One B-rep face of a CAD part: STEP entity #219.
In plain terms, the planar face has unit normal (1, 0, 0).
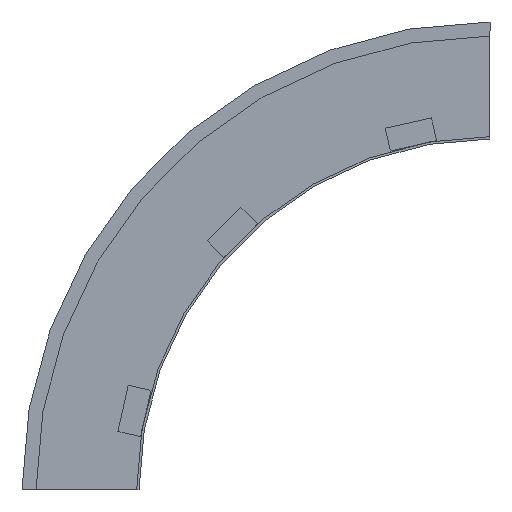
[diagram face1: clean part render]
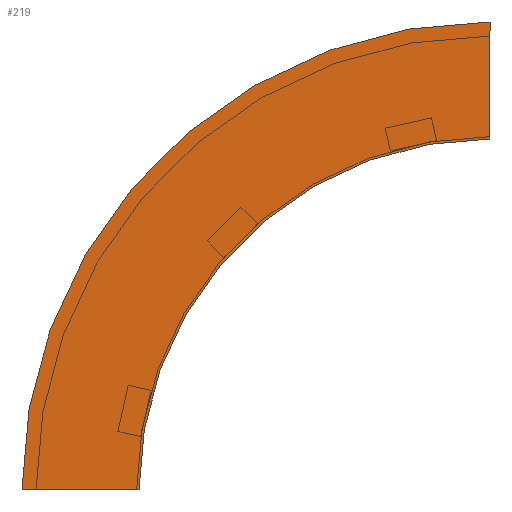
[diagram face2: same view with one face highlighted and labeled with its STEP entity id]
Its self-contained STEP definition (entity closure, numbers rounded to 3 decimals):
#1 = DIRECTION ( 'NONE',  ( 1., 0., 0. ) ) ;
#32 = EDGE_CURVE ( 'NONE', #142, #307, #150, .T. ) ;
#39 = AXIS2_PLACEMENT_3D ( 'NONE', #148, #1, #452 ) ;
#40 = ORIENTED_EDGE ( 'NONE', *, *, #32, .F. ) ;
#47 = VERTEX_POINT ( 'NONE', #563 ) ;
#54 = CARTESIAN_POINT ( 'NONE',  ( 0., -300., 300. ) ) ;
#71 = DIRECTION ( 'NONE',  ( 0., 0., -1. ) ) ;
#96 = AXIS2_PLACEMENT_3D ( 'NONE', #151, #562, #71 ) ;
#125 = EDGE_CURVE ( 'NONE', #47, #142, #304, .T. ) ;
#126 = LINE ( 'NONE', #477, #436 ) ;
#142 = VERTEX_POINT ( 'NONE', #54 ) ;
#148 = CARTESIAN_POINT ( 'NONE',  ( 0., -300., 0. ) ) ;
#150 = LINE ( 'NONE', #410, #328 ) ;
#151 = CARTESIAN_POINT ( 'NONE',  ( 0., 0., 0. ) ) ;
#176 = CIRCLE ( 'NONE', #39, 400. ) ;
#179 = EDGE_CURVE ( 'NONE', #503, #307, #176, .T. ) ;
#195 = EDGE_LOOP ( 'NONE', ( #435, #40, #476, #542 ) ) ;
#197 = CARTESIAN_POINT ( 'NONE',  ( 0., -300., 400. ) ) ;
#219 = ADVANCED_FACE ( 'NONE', ( #515 ), #523, .T. ) ;
#266 = DIRECTION ( 'NONE',  ( 0., 1., 0. ) ) ;
#304 = CIRCLE ( 'NONE', #329, 300. ) ;
#307 = VERTEX_POINT ( 'NONE', #197 ) ;
#328 = VECTOR ( 'NONE', #377, 1000. ) ;
#329 = AXIS2_PLACEMENT_3D ( 'NONE', #543, #546, #266 ) ;
#377 = DIRECTION ( 'NONE',  ( 0., 0., 1. ) ) ;
#410 = CARTESIAN_POINT ( 'NONE',  ( 0., -300., 300. ) ) ;
#435 = ORIENTED_EDGE ( 'NONE', *, *, #179, .T. ) ;
#436 = VECTOR ( 'NONE', #577, 1000. ) ;
#452 = DIRECTION ( 'NONE',  ( 0., 1., 0. ) ) ;
#476 = ORIENTED_EDGE ( 'NONE', *, *, #125, .F. ) ;
#477 = CARTESIAN_POINT ( 'NONE',  ( 0., 0., 0. ) ) ;
#483 = CARTESIAN_POINT ( 'NONE',  ( 0., 100., 0. ) ) ;
#497 = EDGE_CURVE ( 'NONE', #47, #503, #126, .T. ) ;
#503 = VERTEX_POINT ( 'NONE', #483 ) ;
#515 = FACE_OUTER_BOUND ( 'NONE', #195, .T. ) ;
#523 = PLANE ( 'NONE',  #96 ) ;
#542 = ORIENTED_EDGE ( 'NONE', *, *, #497, .T. ) ;
#543 = CARTESIAN_POINT ( 'NONE',  ( 0., -300., 0. ) ) ;
#546 = DIRECTION ( 'NONE',  ( 1., 0., 0. ) ) ;
#562 = DIRECTION ( 'NONE',  ( 1., 0., 0. ) ) ;
#563 = CARTESIAN_POINT ( 'NONE',  ( 0., 0., 0. ) ) ;
#577 = DIRECTION ( 'NONE',  ( 0., 1., 0. ) ) ;
